VERSION 5.7 ;
  NOWIREEXTENSIONATPIN ON ;
  DIVIDERCHAR "/" ;
  BUSBITCHARS "[]" ;

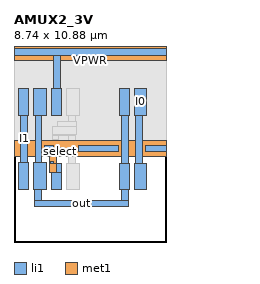
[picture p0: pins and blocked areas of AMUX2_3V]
MACRO AMUX2_3V
  CLASS BLOCK ;
  FOREIGN AMUX2_3V ;
  ORIGIN 0.000 0.000 ;
  SIZE 8.740 BY 10.880 ;
  SYMMETRY X Y ;
  
  PIN I0
    DIRECTION INPUT ;
    USE SIGNAL ;
    ANTENNADIFFAREA 2.527200 ;
    PORT
      LAYER li1 ;
        RECT 6.890 7.240 7.610 8.800 ;
        RECT 6.940 4.520 7.340 7.240 ;
        RECT 6.890 3.000 7.610 4.520 ;
    END
  END I0

  PIN I1
    DIRECTION INPUT ;
    USE SIGNAL ;
    ANTENNADIFFAREA 2.073600 ;
    PORT
      LAYER li1 ;
        RECT 0.280 7.240 0.850 8.800 ;
        RECT 0.400 4.560 0.800 7.240 ;
        RECT 0.280 3.000 0.850 4.560 ;
    END
  END I1

  PIN select
    DIRECTION INPUT ;
    USE SIGNAL ;
    ANTENNAGATEAREA 1.296000 ;
    PORT
      LAYER met1 ;
        RECT 2.450 4.900 2.800 5.440 ;
    END
  END select

  PIN out
    DIRECTION OUTPUT ;
    USE SIGNAL ;
    ANTENNADIFFAREA 4.536000 ;
    PORT
      LAYER li1 ;
        RECT 1.130 7.240 1.850 8.800 ;
        RECT 6.040 7.240 6.610 8.800 ;
        RECT 1.210 4.560 1.600 7.240 ;
        RECT 1.130 3.000 1.850 4.560 ;
        RECT 6.160 4.520 6.560 7.240 ;
        RECT 6.040 3.000 6.610 4.520 ;
        RECT 1.200 2.380 1.600 3.000 ;
        RECT 6.160 2.380 6.560 3.000 ;
        RECT 1.200 2.040 6.560 2.380 ;
    END
  END out

  PIN VGND
    DIRECTION INOUT ;
    USE GROUND ;
    PORT
      LAYER li1 ;
        RECT 1.770 5.180 2.280 5.540 ;
        RECT 3.670 5.180 5.990 5.540 ;
        RECT 7.510 5.180 8.740 5.540 ;
        RECT 2.110 4.520 2.280 4.620 ;
        RECT 2.110 4.500 2.740 4.520 ;
        RECT 2.030 4.000 2.740 4.500 ;
        RECT 2.170 3.000 2.740 4.000 ;
      LAYER met1 ;
        RECT 0.000 4.880 8.740 5.840 ;
        RECT 2.030 4.500 2.420 4.880 ;
        RECT 2.030 4.000 2.450 4.500 ;
    END
  END VGND

  PIN VPWR
    DIRECTION INOUT ;
    USE POWER ;
    PORT
      LAYER li1 ;
        RECT 0.000 10.700 8.740 11.060 ;
        RECT 2.290 8.800 2.690 10.700 ;
        RECT 2.170 7.240 2.740 8.800 ;
      LAYER met1 ;
        RECT 0.000 10.400 8.740 11.360 ;
    END
  END VPWR

  OBS
      LAYER nwell ;
        RECT 0.000 5.820 8.740 11.520 ;
      LAYER li1 ;
        RECT 3.020 7.240 3.740 8.800 ;
        RECT 3.100 6.900 3.500 7.240 ;
        RECT 2.470 6.880 3.500 6.900 ;
        RECT 2.470 6.600 3.600 6.880 ;
        RECT 2.220 6.160 3.600 6.600 ;
        RECT 2.220 6.100 3.500 6.160 ;
        RECT 2.220 5.880 2.570 6.100 ;
        RECT 2.920 6.080 3.500 6.100 ;
        RECT 3.100 4.520 3.500 6.080 ;
        RECT 3.020 3.000 3.740 4.520 ;
  END
END AMUX2_3V

END LIBRARY
